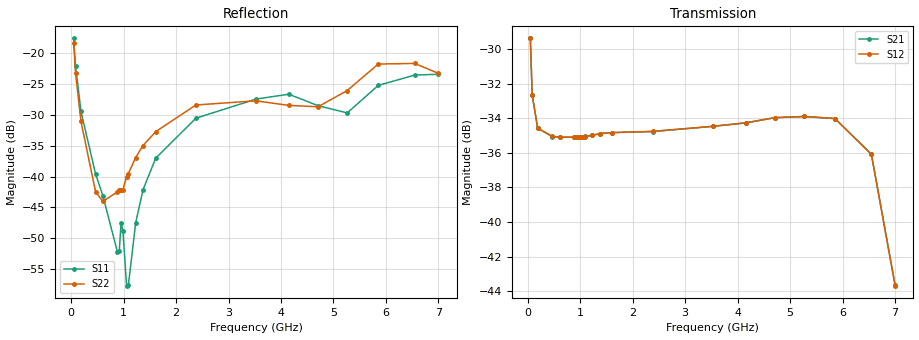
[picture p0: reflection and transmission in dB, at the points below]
! Integrated Device Technology
! Corporate Headquarters
! 6024 Silver Creek Valley Road
! San Jose, CA 95138  USA
! Phone:  1-408-284-8200
! Toll Free:  1-800-223-1366
! Webpage:  http://www.idt.com/
! Timing and RF Division
! 515 Groton Road, Suite 102
! Westford, MA 01886-6024
! Device:  F2258
! Description: Voltage Variable RF Attenuator
! Frequency:  50.0 -  6000.00 MHz
! Package:  3x3 mm Thin QFN Plastic Package: 16 pin
! Ports:  2 RF, 2 DC
!  Pin  1  = NC
!  Pin  2  = NC
!  Pin  3  = RF2  = Port 2
!  Pin  4  = GND
!  Pin  5  = Vdd
!  Pin  6  = NC
!  Pin  7  = VCTRL
!  Pin  8  = NC
!  Pin  9  = GND
!  Pin 10  = RF1  = Port 1
!  Pin 11  = NC
!  Pin 12  = NC
!  Pin 13  = NC
!  Pin 14  = NC
!  Pin 15  = NC
!  Pin 16  = NC
! Vcntrl:  2.040 Volts
! Vdd:  +3.300 Volts
! Current:  1.154 mA
! Data:  The device was measured on a the F2258 evaluation board which has
!  individual transmission lines to the RF pins.  Data was collected
!  using a calibrated network analyzer.  The evaluation board was
!  de-embedded using a TRL calibration technique.
!  The reference plane is the edge of the package pin.
! Misc:  SN 10
!  Action Tracker AT0285
! Date Measured:  2014-12-10
! Date:  2016-01-13  MJV
! Note:
!  Integrated Device Technology supplies this data as a sample of measured
!  data at the package pin for this product.  Your particular data for this
!  product may vary.
!  Data was taken at 25 degrees C.
!  Integrated Device Technology reserves the right to change this data at anytime.
!Freq_(GHz)  S11M_(dB)  S11P_(deg)  S21M_(dB)  S21P_(deg)  S12M_(dB)  S12P_(deg)  S22M_(dB)  S22P_(deg)
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# GHz S dB R 50
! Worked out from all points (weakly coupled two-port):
!   201 points, 50 MHz to 7 GHz, reference 50 ohm
!   highest |S21| = -29.39 dB at 50 MHz (marker M1); lowest = -43.6 dB at 7 GHz (marker M2)
!   lowest |S11| = -57.7 dB at 1.058 GHz (marker M3), VSWR 1.00, Z = 49.9 + j0.0544 ohm
!   |S11| at or under -10 dB: start of sweep to end of sweep
!   |S22| runs from -44.0 to -18.3 dB; largest |S21 - S12| = 7.2e-05
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0.05  -17.55 -111.0  -29.39 -67.1  -29.39 -67.1  -18.32 -109.0
0.08475  -21.97 -107.4  -32.64 -47.6  -32.65 -47.6  -23.14 -101.4
0.189  -29.42 -109.3  -34.57 -24.2  -34.57 -24.1  -31.04 -91.6
0.467  -39.57 -120.3  -35.06 -11.7  -35.05 -11.7  -42.47 -46.3
0.606  -43.11 -125.5  -35.10 -10.0  -35.10 -10.0  -44.03 -9.9
0.884  -52.25 166.2  -35.10 -8.6  -35.10 -8.6  -42.47 30.3
0.91875  -52.06 150.6  -35.10 -8.5  -35.10 -8.5  -42.19 32.2
0.9535  -47.56 -162.3  -35.11 -8.4  -35.11 -8.4  -42.22 57.9
0.98825  -48.77 -174.1  -35.09 -8.3  -35.09 -8.3  -42.11 53.7
1.05775  -57.72 155.2  -35.07 -8.2  -35.07 -8.2  -40.06 46.5
1.0925  -57.60 120.0  -35.05 -8.2  -35.06 -8.2  -39.50 45.5
1.2315  -47.49 46.9  -34.99 -8.3  -34.99 -8.2  -36.90 37.3
1.3705  -42.17 36.8  -34.89 -8.7  -34.89 -8.7  -34.96 34.2
1.61375  -37.00 32.7  -34.83 -10.0  -34.83 -10.0  -32.70 29.3
2.37825  -30.52 48.1  -34.77 -13.8  -34.76 -13.8  -28.37 29.0
3.525  -27.41 91.6  -34.47 -20.5  -34.47 -20.5  -27.69 56.0
4.1505  -26.62 104.9  -34.27 -25.0  -34.27 -25.0  -28.44 65.7
4.7065  -28.49 95.6  -33.97 -29.7  -33.97 -29.7  -28.66 47.7
5.2625  -29.66 54.3  -33.90 -35.9  -33.90 -35.8  -26.02 10.9
5.85325  -25.19 29.8  -34.02 -46.3  -34.02 -46.3  -21.72 -8.8
6.54825  -23.51 45.0  -36.08 -66.5  -36.08 -66.6  -21.62 -42.9
7  -23.38 84.4  -43.63 -62.3  -43.67 -61.7  -23.24 -128.3
